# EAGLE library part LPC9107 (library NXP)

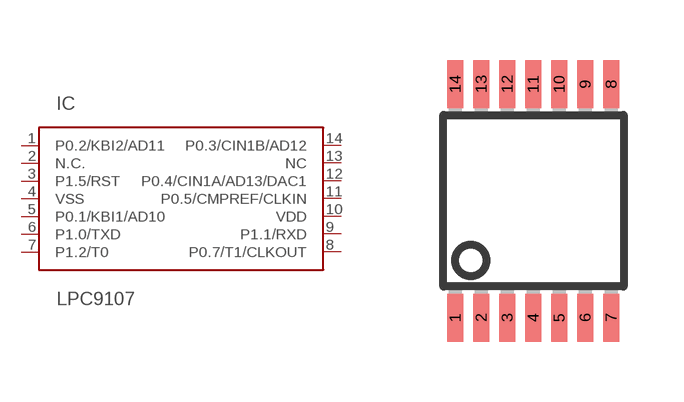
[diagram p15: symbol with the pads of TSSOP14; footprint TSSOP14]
Designator prefix IC

## LPC9107  [TSSOP14]
1  P0.2/KBI2/AD11
2  N.C.  nc
3  P1.5/RST
4  VSS
5  P0.1/KBI1/AD10
6  P1.0/TXD
7  P1.2/T0
8  P0.7/T1/CLKOUT
9  P1.1/RXD
10  VDD
11  P0.5/CMPREF/CLKIN
12  P0.4/CIN1A/AD13/DAC1
13  NC  nc
14  P0.3/CIN1B/AD12

## Footprint TSSOP14 (pad centres in mm)
smd 0.4 x 1.2: 1 -2.275,-2.925; 2 -1.625,-2.925; 3 -0.975,-2.925; 4 -0.325,-2.925; 5 0.325,-2.925; 6 0.975,-2.925; 7 1.625,-2.925; 8 1.625,2.925; 9 0.975,2.925; 10 0.325,2.925; 11 -0.325,2.925; 12 -0.975,2.925; 13 -1.625,2.925; 14 -2.275,2.925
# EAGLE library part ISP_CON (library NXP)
In System Programming connector for Philips ARM devices - /ISP and /RST must have pull up on uC side - /ISP is P0.14 on the LPC21xx chips - RxD is receive from uC, uC should driveTxD - 3,3V and 0V is supplied by the uC board - key is missing pin on a header, corresponding filled in the female plug for a ASP (anti smoke protection:)

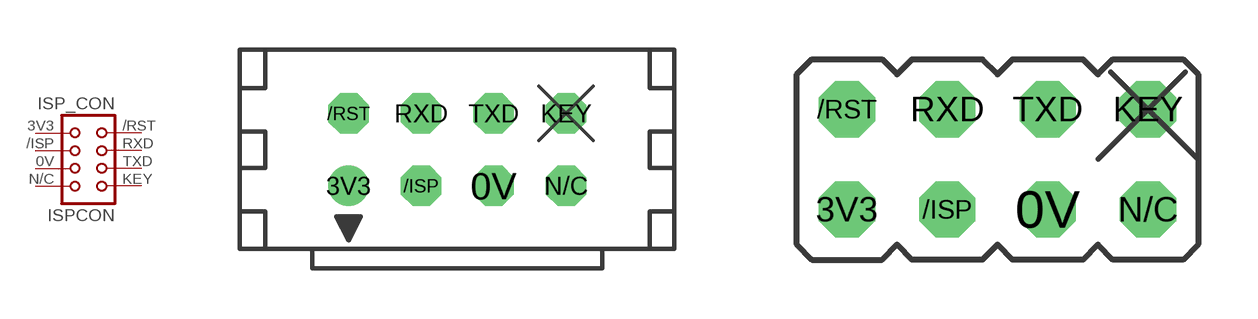
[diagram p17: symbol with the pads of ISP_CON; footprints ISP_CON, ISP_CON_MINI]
Designator prefix ISPCON

## ISP_CON  [ISP_CON]
0V  0V  pas
3V3  3V3  pas
/ISP  /ISP  pas
/RST  /RST  pas
KEY  KEY  pas
N/C  N/C  pas
RXD  RXD  pas
TXD  TXD  pas

## ISP_CONMINI  [ISP_CON_MINI]
Pads as for ISP_CON

## Footprint ISP_CON (pad centres in mm)
drill 0.914 octagon: 0V 1.27,-1.27; /ISP -1.27,-1.27; /RST -3.81,1.27; KEY 3.81,1.27; N/C 3.81,-1.27; RXD -1.27,1.27; TXD 1.27,1.27
drill 0.914 round: 3V3 -3.81,-1.27

## Footprint ISP_CON_MINI (pad centres in mm)
JUMPER
drill 0.914 octagon: 0V 1.27,-1.27; 3V3 -3.81,-1.27; /ISP -1.27,-1.27; /RST -3.81,1.27; KEY 3.81,1.27; N/C 3.81,-1.27; RXD -1.27,1.27; TXD 1.27,1.27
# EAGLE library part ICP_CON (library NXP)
ICP (In Circuit Programing ) connector for Philips LPC9XX 8052 devices

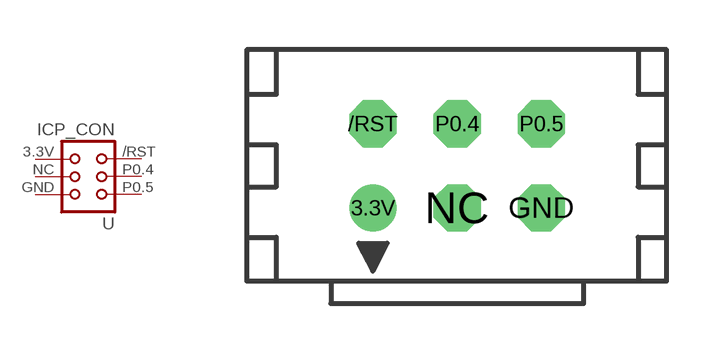
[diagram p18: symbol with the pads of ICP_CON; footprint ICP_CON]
Designator prefix -

## ICP_CON  [ICP_CON]
3.3V  3.3V  pas
/RST  /RST  pas
GND  GND  pas
NC  NC  pas
P0.4  P0.4  pas
P0.5  P0.5  pas

## Footprint ICP_CON (pad centres in mm)
drill 0.914 round: 3.3V -2.54,-1.27
drill 0.914 octagon: /RST -2.54,1.27; GND 2.54,-1.27; NC 0,-1.27; P0.4 0,1.27; P0.5 2.54,1.27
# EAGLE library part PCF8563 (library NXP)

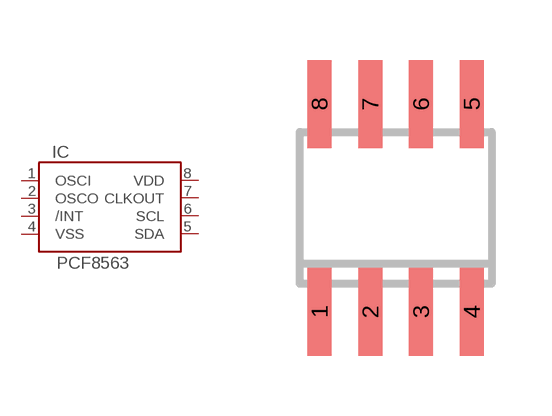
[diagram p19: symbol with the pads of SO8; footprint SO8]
Designator prefix IC

## PCF8563T  [SO8]
1  OSCI
2  OSCO
3  /INT
4  VSS
5  SDA
6  SCL
7  CLKOUT
8  VDD

## Footprint SO8 (pad centres in mm)
smd 0.6 x 2.2: 1 -1.905,-2.6; 2 -0.635,-2.6; 3 0.635,-2.6; 4 1.905,-2.6; 5 1.905,2.6; 6 0.635,2.6; 7 -0.635,2.6; 8 -1.905,2.6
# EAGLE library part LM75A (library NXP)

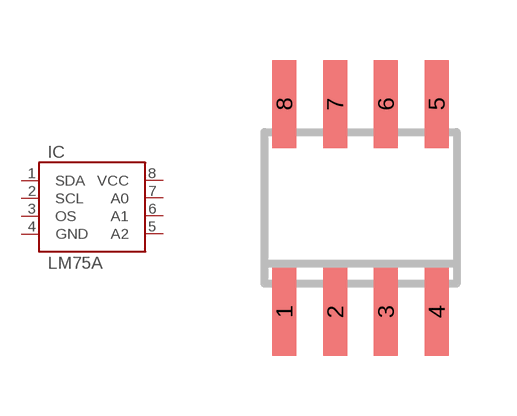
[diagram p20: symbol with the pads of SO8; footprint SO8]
Designator prefix IC

## LM75A  [SO8]
1  SDA
2  SCL
3  OS
4  GND
5  A2
6  A1
7  A0
8  VCC

## Footprint SO8 (pad centres in mm)
smd 0.6 x 2.2: 1 -1.905,-2.6; 2 -0.635,-2.6; 3 0.635,-2.6; 4 1.905,-2.6; 5 1.905,2.6; 6 0.635,2.6; 7 -0.635,2.6; 8 -1.905,2.6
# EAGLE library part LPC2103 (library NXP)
LPC2101/2102/2103 microcontroler from Philips

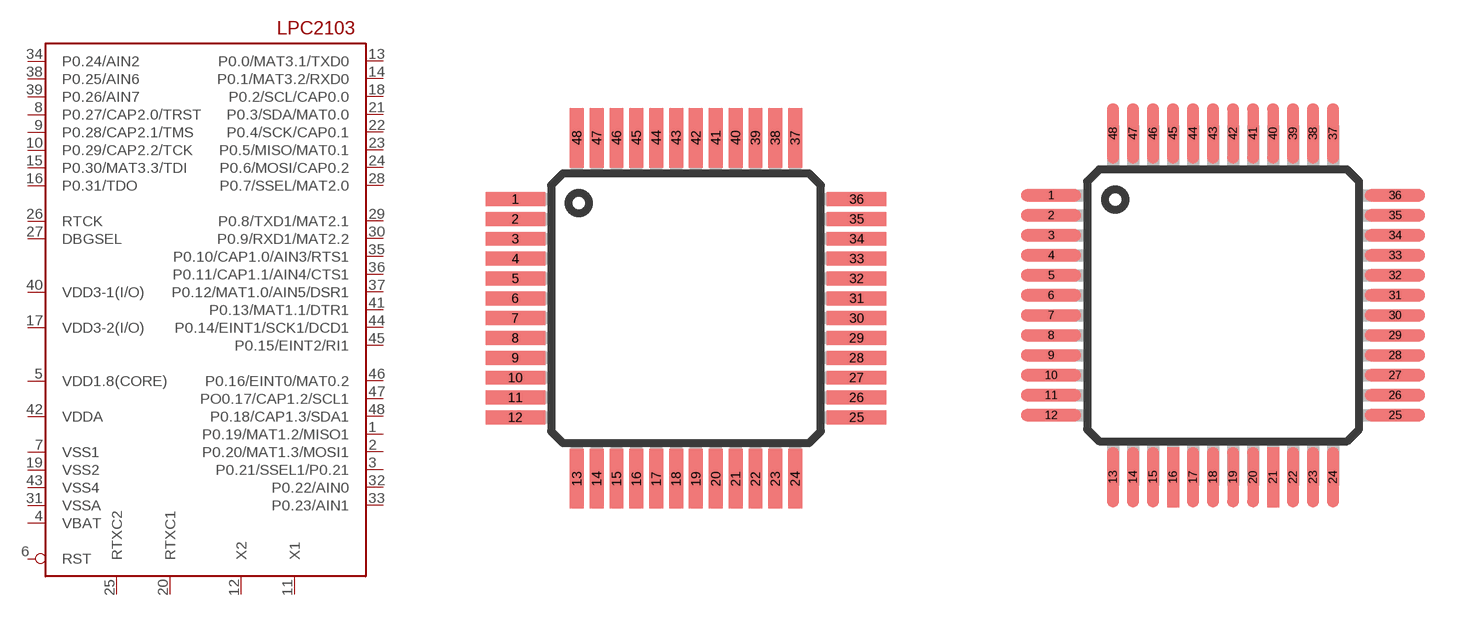
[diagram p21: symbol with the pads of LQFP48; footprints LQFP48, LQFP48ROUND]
Designator prefix IC

## LPC2103  [LQFP48]
1  P0.19/MAT1.2/MISO1
2  P0.20/MAT1.3/MOSI1
3  P0.21/SSEL1/P0.21
4  VBAT
5  VDD1.8(CORE)
6  RST
7  VSS1
8  P0.27/CAP2.0/TRST
9  P0.28/CAP2.1/TMS
10  P0.29/CAP2.2/TCK
11  X1
12  X2
13  P0.0/MAT3.1/TXD0
14  P0.1/MAT3.2/RXD0
15  P0.30/MAT3.3/TDI
16  P0.31/TDO
17  VDD3-2(I/O)
18  P0.2/SCL/CAP0.0
19  VSS2
20  RTXC1
21  P0.3/SDA/MAT0.0
22  P0.4/SCK/CAP0.1
23  P0.5/MISO/MAT0.1
24  P0.6/MOSI/CAP0.2
25  RTXC2
26  RTCK
27  DBGSEL
28  P0.7/SSEL/MAT2.0
29  P0.8/TXD1/MAT2.1
30  P0.9/RXD1/MAT2.2
31  VSSA
32  P0.22/AIN0
33  P0.23/AIN1
34  P0.24/AIN2
35  P0.10/CAP1.0/AIN3/RTS1
36  P0.11/CAP1.1/AIN4/CTS1
37  P0.12/MAT1.0/AIN5/DSR1
38  P0.25/AIN6
39  P0.26/AIN7
40  VDD3-1(I/O)
41  P0.13/MAT1.1/DTR1
42  VDDA
43  VSS4
44  P0.14/EINT1/SCK1/DCD1
45  P0.15/EINT2/RI1
46  P0.16/EINT0/MAT0.2
47  PO0.17/CAP1.2/SCL1
48  P0.18/CAP1.3/SDA1

## LPC2103ROUND  [LQFP48ROUND]
Pads as for LQFP48

## Footprint LQFP48 (pad centres in mm)
smd 1.5 x 0.35: 1 -4.3,2.75; 2 -4.3,2.25; 3 -4.3,1.75; 4 -4.3,1.25; 5 -4.3,0.75; 6 -4.3,0.25; 7 -4.3,-0.25; 8 -4.3,-0.75; 9 -4.3,-1.25; 10 -4.3,-1.75; 11 -4.3,-2.25; 12 -4.3,-2.75; 25 4.3,-2.75; 26 4.3,-2.25; 27 4.3,-1.75; 28 4.3,-1.25; 29 4.3,-0.75; 30 4.3,-0.25; 31 4.3,0.25; 32 4.3,0.75; 33 4.3,1.25; 34 4.3,1.75; 35 4.3,2.25; 36 4.3,2.75
smd 0.35 x 1.5: 13 -2.75,-4.3; 14 -2.25,-4.3; 15 -1.75,-4.3; 16 -1.25,-4.3; 17 -0.75,-4.3; 18 -0.25,-4.3; 19 0.25,-4.3; 20 0.75,-4.3; 21 1.25,-4.3; 22 1.75,-4.3; 23 2.25,-4.3; 24 2.75,-4.3; 37 2.75,4.3; 38 2.25,4.3; 39 1.75,4.3; 40 1.25,4.3; 41 0.75,4.3; 42 0.25,4.3; 43 -0.25,4.3; 44 -0.75,4.3; 45 -1.25,4.3; 46 -1.75,4.3; 47 -2.25,4.3; 48 -2.75,4.3

## Footprint LQFP48ROUND (pad centres in mm)
smd 1.5 x 0.3: 1 -4.3,2.75; 2 -4.3,2.25; 3 -4.3,1.75; 4 -4.3,1.25; 5 -4.3,0.75; 6 -4.3,0.25; 7 -4.3,-0.25; 8 -4.3,-0.75; 9 -4.3,-1.25; 10 -4.3,-1.75; 11 -4.3,-2.25; 12 -4.3,-2.75; 25 4.3,-2.75; 26 4.3,-2.25; 27 4.3,-1.75; 28 4.3,-1.25; 29 4.3,-0.75; 30 4.3,-0.25; 31 4.3,0.25; 32 4.3,0.75; 33 4.3,1.25; 34 4.3,1.75; 35 4.3,2.25; 36 4.3,2.75
smd 0.3 x 1.5: 13 -2.75,-4.3; 14 -2.25,-4.3; 15 -1.75,-4.3; 16 -1.25,-4.3; 17 -0.75,-4.3; 18 -0.25,-4.3; 19 0.25,-4.3; 20 0.75,-4.3; 21 1.25,-4.3; 22 1.75,-4.3; 23 2.25,-4.3; 24 2.75,-4.3; 37 2.75,4.3; 38 2.25,4.3; 39 1.75,4.3; 40 1.25,4.3; 41 0.75,4.3; 42 0.25,4.3; 43 -0.25,4.3; 44 -0.75,4.3; 45 -1.25,4.3; 46 -1.75,4.3; 47 -2.25,4.3; 48 -2.75,4.3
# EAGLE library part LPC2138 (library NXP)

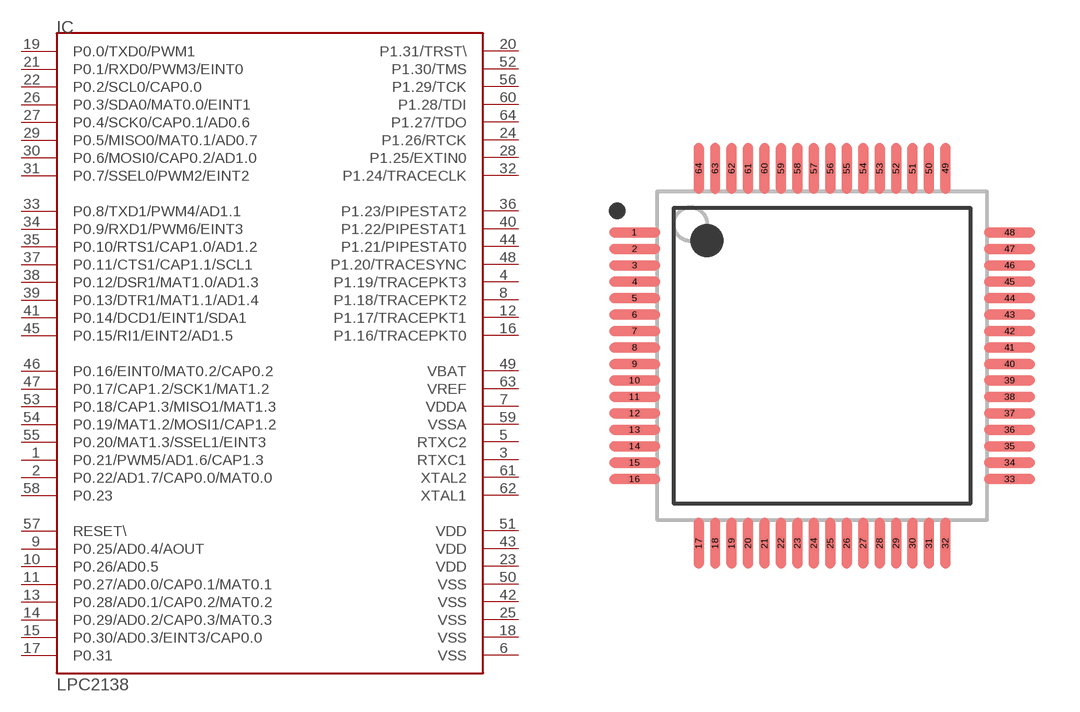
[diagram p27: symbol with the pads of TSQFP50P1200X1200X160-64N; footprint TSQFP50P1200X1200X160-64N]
Designator prefix IC

## LPC2138FBD64  [TSQFP50P1200X1200X160-64N]
1  P0.21/PWM5/AD1.6/CAP1.3
2  P0.22/AD1.7/CAP0.0/MAT0.0
3  RTXC1  in
4  P1.19/TRACEPKT3
5  RTXC2  out
6  VSS  pwr
7  VDDA  pwr
8  P1.18/TRACEPKT2
9  P0.25/AD0.4/AOUT
10  P0.26/AD0.5
11  P0.27/AD0.0/CAP0.1/MAT0.1
12  P1.17/TRACEPKT1
13  P0.28/AD0.1/CAP0.2/MAT0.2
14  P0.29/AD0.2/CAP0.3/MAT0.3
15  P0.30/AD0.3/EINT3/CAP0.0
16  P1.16/TRACEPKT0
17  P0.31
18  VSS  pwr
19  P0.0/TXD0/PWM1
20  P1.31/TRST\
21  P0.1/RXD0/PWM3/EINT0
22  P0.2/SCL0/CAP0.0
23  VDD  pwr
24  P1.26/RTCK
25  VSS  pwr
26  P0.3/SDA0/MAT0.0/EINT1
27  P0.4/SCK0/CAP0.1/AD0.6
28  P1.25/EXTIN0
29  P0.5/MISO0/MAT0.1/AD0.7
30  P0.6/MOSI0/CAP0.2/AD1.0
31  P0.7/SSEL0/PWM2/EINT2
32  P1.24/TRACECLK
33  P0.8/TXD1/PWM4/AD1.1
34  P0.9/RXD1/PWM6/EINT3
35  P0.10/RTS1/CAP1.0/AD1.2
36  P1.23/PIPESTAT2
37  P0.11/CTS1/CAP1.1/SCL1
38  P0.12/DSR1/MAT1.0/AD1.3
39  P0.13/DTR1/MAT1.1/AD1.4
40  P1.22/PIPESTAT1
41  P0.14/DCD1/EINT1/SDA1
42  VSS  pwr
43  VDD  pwr
44  P1.21/PIPESTAT0
45  P0.15/RI1/EINT2/AD1.5
46  P0.16/EINT0/MAT0.2/CAP0.2
47  P0.17/CAP1.2/SCK1/MAT1.2
48  P1.20/TRACESYNC
49  VBAT  pwr
50  VSS  pwr
51  VDD  pwr
52  P1.30/TMS
53  P0.18/CAP1.3/MISO1/MAT1.3
54  P0.19/MAT1.2/MOSI1/CAP1.2
55  P0.20/MAT1.3/SSEL1/EINT3
56  P1.29/TCK
57  RESET\  in
58  P0.23
59  VSSA  pwr
60  P1.28/TDI
61  XTAL2  out
62  XTAL1  in
63  VREF  in
64  P1.27/TDO

## Footprint TSQFP50P1200X1200X160-64N (pad centres in mm)
smd 1.55 x 0.3: 1 -5.7,3.75; 2 -5.7,3.25; 3 -5.7,2.75; 4 -5.7,2.25; 5 -5.7,1.75; 6 -5.7,1.25; 7 -5.7,0.75; 8 -5.7,0.25; 9 -5.7,-0.25; 10 -5.7,-0.75; 11 -5.7,-1.25; 12 -5.7,-1.75; 13 -5.7,-2.25; 14 -5.7,-2.75; 15 -5.7,-3.25; 16 -5.7,-3.75; 33 5.7,-3.75; 34 5.7,-3.25; 35 5.7,-2.75; 36 5.7,-2.25; 37 5.7,-1.75; 38 5.7,-1.25; 39 5.7,-0.75; 40 5.7,-0.25; 41 5.7,0.25; 42 5.7,0.75; 43 5.7,1.25; 44 5.7,1.75; 45 5.7,2.25; 46 5.7,2.75; 47 5.7,3.25; 48 5.7,3.75
smd 0.3 x 1.55: 17 -3.75,-5.7; 18 -3.25,-5.7; 19 -2.75,-5.7; 20 -2.25,-5.7; 21 -1.75,-5.7; 22 -1.25,-5.7; 23 -0.75,-5.7; 24 -0.25,-5.7; 25 0.25,-5.7; 26 0.75,-5.7; 27 1.25,-5.7; 28 1.75,-5.7; 29 2.25,-5.7; 30 2.75,-5.7; 31 3.25,-5.7; 32 3.75,-5.7; 49 3.75,5.7; 50 3.25,5.7; 51 2.75,5.7; 52 2.25,5.7; 53 1.75,5.7; 54 1.25,5.7; 55 0.75,5.7; 56 0.25,5.7; 57 -0.25,5.7; 58 -0.75,5.7; 59 -1.25,5.7; 60 -1.75,5.7; 61 -2.25,5.7; 62 -2.75,5.7; 63 -3.25,5.7; 64 -3.75,5.7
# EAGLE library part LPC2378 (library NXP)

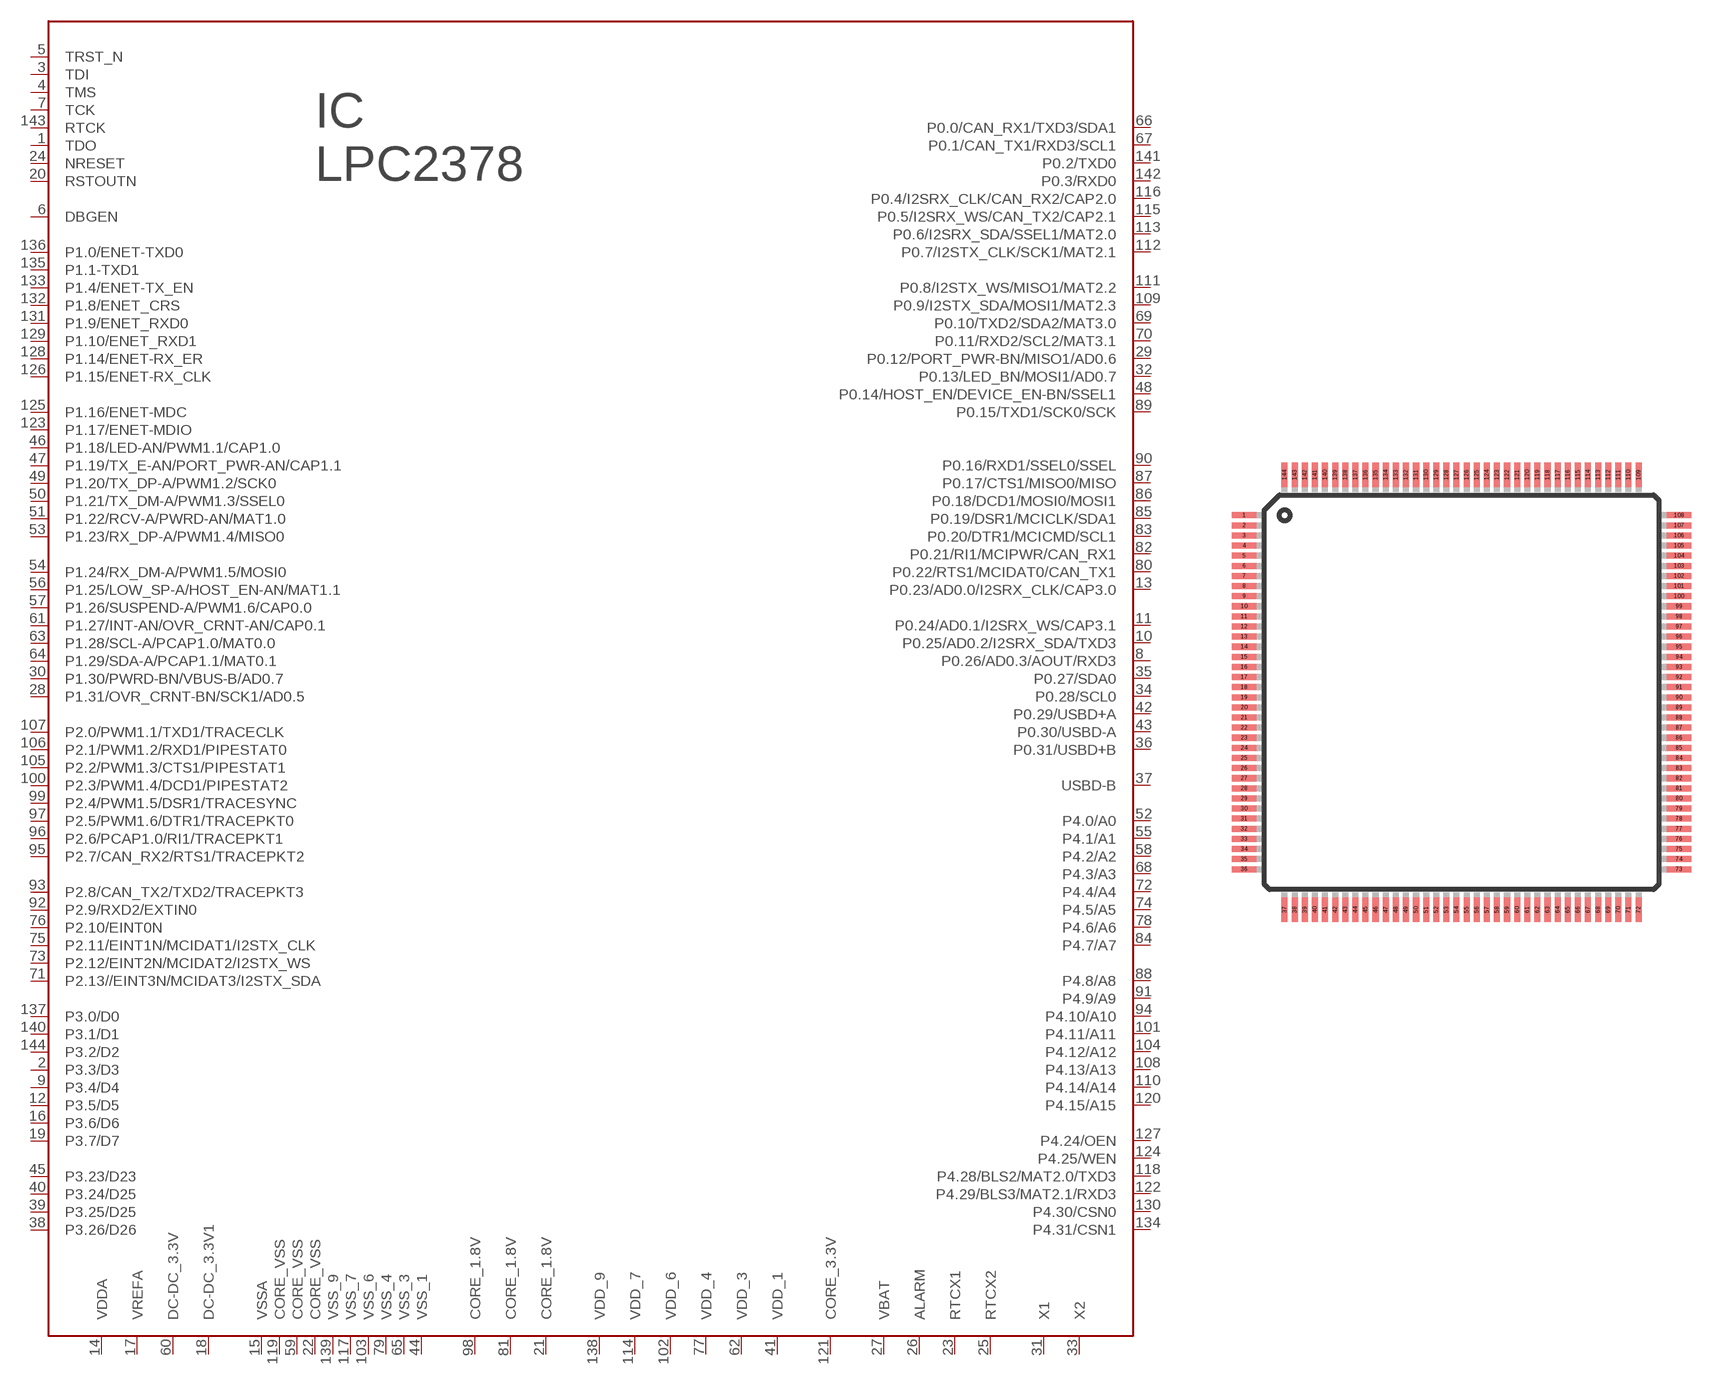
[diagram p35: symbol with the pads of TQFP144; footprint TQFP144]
Designator prefix IC

## LPC2378  [TQFP144]
1  TDO
2  P3.3/D3
3  TDI
4  TMS
5  TRST_N
6  DBGEN
7  TCK
8  P0.26/AD0.3/AOUT/RXD3
9  P3.4/D4
10  P0.25/AD0.2/I2SRX_SDA/TXD3
11  P0.24/AD0.1/I2SRX_WS/CAP3.1
12  P3.5/D5
13  P0.23/AD0.0/I2SRX_CLK/CAP3.0
14  VDDA
15  VSSA
16  P3.6/D6
17  VREFA
18  DC-DC_3.3V1
19  P3.7/D7
20  RSTOUTN
21  CORE_1.8V
22  CORE_VSS
23  RTCX1
24  NRESET
25  RTCX2
26  ALARM
27  VBAT
28  P1.31/OVR_CRNT-BN/SCK1/AD0.5
29  P0.12/PORT_PWR-BN/MISO1/AD0.6
30  P1.30/PWRD-BN/VBUS-B/AD0.7
31  X1
32  P0.13/LED_BN/MOSI1/AD0.7
33  X2
34  P0.28/SCL0
35  P0.27/SDA0
36  P0.31/USBD+B
37  USBD-B
38  P3.26/D26
39  P3.25/D25
40  P3.24/D25
41  VDD_1
42  P0.29/USBD+A
43  P0.30/USBD-A
44  VSS_1
45  P3.23/D23
46  P1.18/LED-AN/PWM1.1/CAP1.0
47  P1.19/TX_E-AN/PORT_PWR-AN/CAP1.1
48  P0.14/HOST_EN/DEVICE_EN-BN/SSEL1
49  P1.20/TX_DP-A/PWM1.2/SCK0
50  P1.21/TX_DM-A/PWM1.3/SSEL0
51  P1.22/RCV-A/PWRD-AN/MAT1.0
52  P4.0/A0
53  P1.23/RX_DP-A/PWM1.4/MISO0
54  P1.24/RX_DM-A/PWM1.5/MOSI0
55  P4.1/A1
56  P1.25/LOW_SP-A/HOST_EN-AN/MAT1.1
57  P1.26/SUSPEND-A/PWM1.6/CAP0.0
58  P4.2/A2
59  CORE_VSS
60  DC-DC_3.3V
61  P1.27/INT-AN/OVR_CRNT-AN/CAP0.1
62  VDD_3
63  P1.28/SCL-A/PCAP1.0/MAT0.0
64  P1.29/SDA-A/PCAP1.1/MAT0.1
65  VSS_3
66  P0.0/CAN_RX1/TXD3/SDA1
67  P0.1/CAN_TX1/RXD3/SCL1
68  P4.3/A3
69  P0.10/TXD2/SDA2/MAT3.0
70  P0.11/RXD2/SCL2/MAT3.1
71  P2.13//EINT3N/MCIDAT3/I2STX_SDA
72  P4.4/A4
73  P2.12/EINT2N/MCIDAT2/I2STX_WS
74  P4.5/A5
75  P2.11/EINT1N/MCIDAT1/I2STX_CLK
76  P2.10/EINT0N
77  VDD_4
78  P4.6/A6
79  VSS_4
80  P0.22/RTS1/MCIDAT0/CAN_TX1
81  CORE_1.8V
82  P0.21/RI1/MCIPWR/CAN_RX1
83  P0.20/DTR1/MCICMD/SCL1
84  P4.7/A7
85  P0.19/DSR1/MCICLK/SDA1
86  P0.18/DCD1/MOSI0/MOSI1
87  P0.17/CTS1/MISO0/MISO
88  P4.8/A8
89  P0.15/TXD1/SCK0/SCK
90  P0.16/RXD1/SSEL0/SSEL
91  P4.9/A9
92  P2.9/RXD2/EXTIN0
93  P2.8/CAN_TX2/TXD2/TRACEPKT3
94  P4.10/A10
95  P2.7/CAN_RX2/RTS1/TRACEPKT2
96  P2.6/PCAP1.0/RI1/TRACEPKT1
97  P2.5/PWM1.6/DTR1/TRACEPKT0
98  CORE_1.8V
99  P2.4/PWM1.5/DSR1/TRACESYNC
100  P2.3/PWM1.4/DCD1/PIPESTAT2
101  P4.11/A11
102  VDD_6
103  VSS_6
104  P4.12/A12
105  P2.2/PWM1.3/CTS1/PIPESTAT1
106  P2.1/PWM1.2/RXD1/PIPESTAT0
107  P2.0/PWM1.1/TXD1/TRACECLK
108  P4.13/A13
109  P0.9/I2STX_SDA/MOSI1/MAT2.3
110  P4.14/A14
111  P0.8/I2STX_WS/MISO1/MAT2.2
112  P0.7/I2STX_CLK/SCK1/MAT2.1
113  P0.6/I2SRX_SDA/SSEL1/MAT2.0
114  VDD_7
115  P0.5/I2SRX_WS/CAN_TX2/CAP2.1
116  P0.4/I2SRX_CLK/CAN_RX2/CAP2.0
117  VSS_7
118  P4.28/BLS2/MAT2.0/TXD3
119  CORE_VSS
120  P4.15/A15
121  CORE_3.3V
122  P4.29/BLS3/MAT2.1/RXD3
123  P1.17/ENET-MDIO
124  P4.25/WEN
125  P1.16/ENET-MDC
126  P1.15/ENET-RX_CLK
127  P4.24/OEN
128  P1.14/ENET-RX_ER
129  P1.10/ENET_RXD1
130  P4.30/CSN0
131  P1.9/ENET_RXD0
132  P1.8/ENET_CRS
133  P1.4/ENET-TX_EN
134  P4.31/CSN1
135  P1.1-TXD1
136  P1.0/ENET-TXD0
137  P3.0/D0
138  VDD_9
139  VSS_9
140  P3.1/D1
141  P0.2/TXD0
142  P0.3/RXD0
143  RTCK
144  P3.2/D2

## Footprint TQFP144 (pad centres in mm)
THIN QUAD FLAT PACK
smd 1.2 x 0.3: 1 -10.75,8.75; 2 -10.75,8.25; 3 -10.75,7.75; 4 -10.75,7.25; 5 -10.75,6.75; 6 -10.75,6.25; 7 -10.75,5.75; 8 -10.75,5.25; 9 -10.75,4.75; 10 -10.75,4.25; 11 -10.75,3.75; 12 -10.75,3.25; 13 -10.75,2.75; 14 -10.75,2.25; 15 -10.75,1.75; 16 -10.75,1.25; 17 -10.75,0.75; 18 -10.75,0.25; 19 -10.75,-0.25; 20 -10.75,-0.75; 21 -10.75,-1.25; 22 -10.75,-1.75; 23 -10.75,-2.25; 24 -10.75,-2.75; 25 -10.75,-3.25; 26 -10.75,-3.75; 27 -10.75,-4.25; 28 -10.75,-4.75; 29 -10.75,-5.25; 30 -10.75,-5.75; 31 -10.75,-6.25; 32 -10.75,-6.75; 33 -10.75,-7.25; 34 -10.75,-7.75; 35 -10.75,-8.25; 36 -10.75,-8.75; 73 10.75,-8.75; 74 10.75,-8.25; 75 10.75,-7.75; 76 10.75,-7.25; 77 10.75,-6.75; 78 10.75,-6.25; 79 10.75,-5.75; 80 10.75,-5.25; 81 10.75,-4.75; 82 10.75,-4.25; 83 10.75,-3.75; 84 10.75,-3.25; 85 10.75,-2.75; 86 10.75,-2.25; 87 10.75,-1.75; 88 10.75,-1.25; 89 10.75,-0.75; 90 10.75,-0.25; 91 10.75,0.25; 92 10.75,0.75; 93 10.75,1.25; 94 10.75,1.75; 95 10.75,2.25; 96 10.75,2.75; 97 10.75,3.25; 98 10.75,3.75; 99 10.75,4.25; 100 10.75,4.75; 101 10.75,5.25; 102 10.75,5.75; 103 10.75,6.25; 104 10.75,6.75; 105 10.75,7.25; 106 10.75,7.75; 107 10.75,8.25; 108 10.75,8.75
smd 0.3 x 1.2: 37 -8.75,-10.75; 38 -8.25,-10.75; 39 -7.75,-10.75; 40 -7.25,-10.75; 41 -6.75,-10.75; 42 -6.25,-10.75; 43 -5.75,-10.75; 44 -5.25,-10.75; 45 -4.75,-10.75; 46 -4.25,-10.75; 47 -3.75,-10.75; 48 -3.25,-10.75; 49 -2.75,-10.75; 50 -2.25,-10.75; 51 -1.75,-10.75; 52 -1.25,-10.75; 53 -0.75,-10.75; 54 -0.25,-10.75; 55 0.25,-10.75; 56 0.75,-10.75; 57 1.25,-10.75; 58 1.75,-10.75; 59 2.25,-10.75; 60 2.75,-10.75; 61 3.25,-10.75; 62 3.75,-10.75; 63 4.25,-10.75; 64 4.75,-10.75; 65 5.25,-10.75; 66 5.75,-10.75; 67 6.25,-10.75; 68 6.75,-10.75; 69 7.25,-10.75; 70 7.75,-10.75; 71 8.25,-10.75; 72 8.75,-10.75; 109 8.75,10.75; 110 8.25,10.75; 111 7.75,10.75; 112 7.25,10.75; 113 6.75,10.75; 114 6.25,10.75; 115 5.75,10.75; 116 5.25,10.75; 117 4.75,10.75; 118 4.25,10.75; 119 3.75,10.75; 120 3.25,10.75; 121 2.75,10.75; 122 2.25,10.75; 123 1.75,10.75; 124 1.25,10.75; 125 0.75,10.75; 126 0.25,10.75; 127 -0.25,10.75; 128 -0.75,10.75; 129 -1.25,10.75; 130 -1.75,10.75; 131 -2.25,10.75; 132 -2.75,10.75; 133 -3.25,10.75; 134 -3.75,10.75; 135 -4.25,10.75; 136 -4.75,10.75; 137 -5.25,10.75; 138 -5.75,10.75; 139 -6.25,10.75; 140 -6.75,10.75; 141 -7.25,10.75; 142 -7.75,10.75; 143 -8.25,10.75; 144 -8.75,10.75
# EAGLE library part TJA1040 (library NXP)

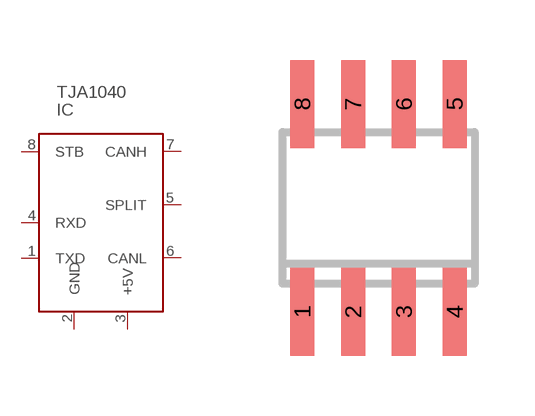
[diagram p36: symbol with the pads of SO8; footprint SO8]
Designator prefix IC

## TJA1040  [SO8]
1  TXD
2  GND
3  +5V
4  RXD
5  SPLIT
6  CANL
7  CANH
8  STB

## Footprint SO8 (pad centres in mm)
smd 0.6 x 2.2: 1 -1.905,-2.6; 2 -0.635,-2.6; 3 0.635,-2.6; 4 1.905,-2.6; 5 1.905,2.6; 6 0.635,2.6; 7 -0.635,2.6; 8 -1.905,2.6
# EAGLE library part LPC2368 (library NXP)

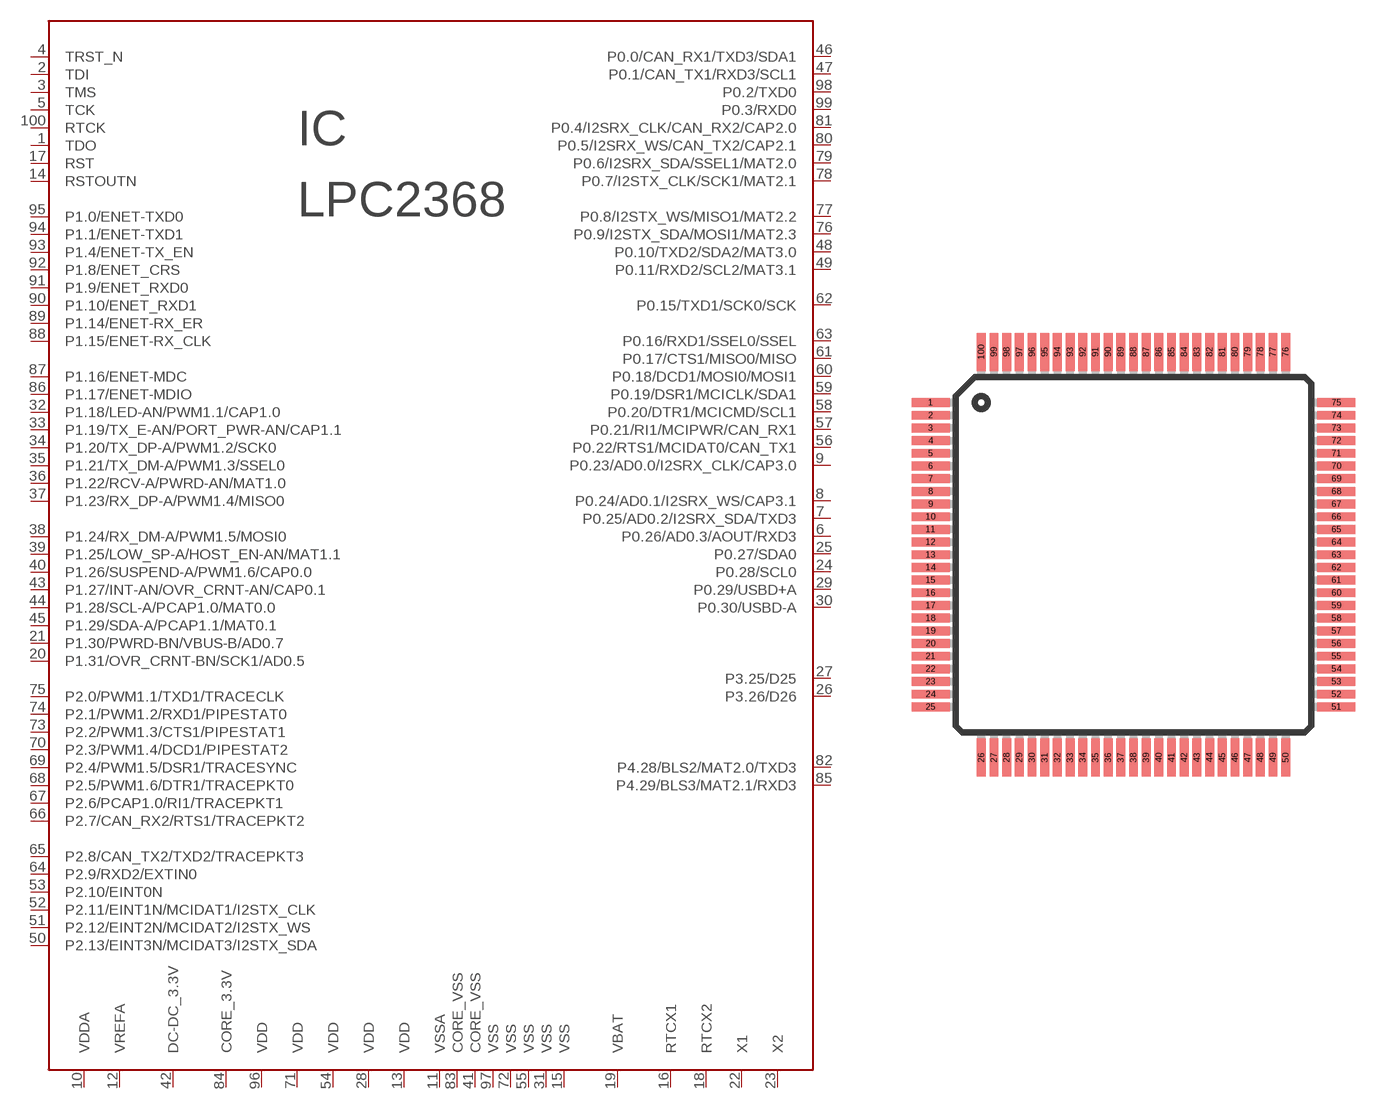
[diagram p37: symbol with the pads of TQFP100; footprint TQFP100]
Designator prefix IC

## LPC2368  [TQFP100]
1  TDO
2  TDI
3  TMS
4  TRST_N
5  TCK
6  P0.26/AD0.3/AOUT/RXD3
7  P0.25/AD0.2/I2SRX_SDA/TXD3
8  P0.24/AD0.1/I2SRX_WS/CAP3.1
9  P0.23/AD0.0/I2SRX_CLK/CAP3.0
10  VDDA
11  VSSA
12  VREFA
13  VDD
14  RSTOUTN
15  VSS
16  RTCX1
17  RST
18  RTCX2
19  VBAT
20  P1.31/OVR_CRNT-BN/SCK1/AD0.5
21  P1.30/PWRD-BN/VBUS-B/AD0.7
22  X1
23  X2
24  P0.28/SCL0
25  P0.27/SDA0
26  P3.26/D26
27  P3.25/D25
28  VDD
29  P0.29/USBD+A
30  P0.30/USBD-A
31  VSS
32  P1.18/LED-AN/PWM1.1/CAP1.0
33  P1.19/TX_E-AN/PORT_PWR-AN/CAP1.1
34  P1.20/TX_DP-A/PWM1.2/SCK0
35  P1.21/TX_DM-A/PWM1.3/SSEL0
36  P1.22/RCV-A/PWRD-AN/MAT1.0
37  P1.23/RX_DP-A/PWM1.4/MISO0
38  P1.24/RX_DM-A/PWM1.5/MOSI0
39  P1.25/LOW_SP-A/HOST_EN-AN/MAT1.1
40  P1.26/SUSPEND-A/PWM1.6/CAP0.0
41  CORE_VSS
42  DC-DC_3.3V
43  P1.27/INT-AN/OVR_CRNT-AN/CAP0.1
44  P1.28/SCL-A/PCAP1.0/MAT0.0
45  P1.29/SDA-A/PCAP1.1/MAT0.1
46  P0.0/CAN_RX1/TXD3/SDA1
47  P0.1/CAN_TX1/RXD3/SCL1
48  P0.10/TXD2/SDA2/MAT3.0
49  P0.11/RXD2/SCL2/MAT3.1
50  P2.13/EINT3N/MCIDAT3/I2STX_SDA
51  P2.12/EINT2N/MCIDAT2/I2STX_WS
52  P2.11/EINT1N/MCIDAT1/I2STX_CLK
53  P2.10/EINT0N
54  VDD
55  VSS
56  P0.22/RTS1/MCIDAT0/CAN_TX1
57  P0.21/RI1/MCIPWR/CAN_RX1
58  P0.20/DTR1/MCICMD/SCL1
59  P0.19/DSR1/MCICLK/SDA1
60  P0.18/DCD1/MOSI0/MOSI1
61  P0.17/CTS1/MISO0/MISO
62  P0.15/TXD1/SCK0/SCK
63  P0.16/RXD1/SSEL0/SSEL
64  P2.9/RXD2/EXTIN0
65  P2.8/CAN_TX2/TXD2/TRACEPKT3
66  P2.7/CAN_RX2/RTS1/TRACEPKT2
67  P2.6/PCAP1.0/RI1/TRACEPKT1
68  P2.5/PWM1.6/DTR1/TRACEPKT0
69  P2.4/PWM1.5/DSR1/TRACESYNC
70  P2.3/PWM1.4/DCD1/PIPESTAT2
71  VDD
72  VSS
73  P2.2/PWM1.3/CTS1/PIPESTAT1
74  P2.1/PWM1.2/RXD1/PIPESTAT0
75  P2.0/PWM1.1/TXD1/TRACECLK
76  P0.9/I2STX_SDA/MOSI1/MAT2.3
77  P0.8/I2STX_WS/MISO1/MAT2.2
78  P0.7/I2STX_CLK/SCK1/MAT2.1
79  P0.6/I2SRX_SDA/SSEL1/MAT2.0
80  P0.5/I2SRX_WS/CAN_TX2/CAP2.1
81  P0.4/I2SRX_CLK/CAN_RX2/CAP2.0
82  P4.28/BLS2/MAT2.0/TXD3
83  CORE_VSS
84  CORE_3.3V
85  P4.29/BLS3/MAT2.1/RXD3
86  P1.17/ENET-MDIO
87  P1.16/ENET-MDC
88  P1.15/ENET-RX_CLK
89  P1.14/ENET-RX_ER
90  P1.10/ENET_RXD1
91  P1.9/ENET_RXD0
92  P1.8/ENET_CRS
93  P1.4/ENET-TX_EN
94  P1.1/ENET-TXD1
95  P1.0/ENET-TXD0
96  VDD
97  VSS
98  P0.2/TXD0
99  P0.3/RXD0
100  RTCK

## Footprint TQFP100 (pad centres in mm)
Thin Quad Flat Package
smd 1.5 x 0.35: 1 -8,6; 2 -8,5.5; 3 -8,5; 4 -8,4.5; 5 -8,4; 6 -8,3.5; 7 -8,3; 8 -8,2.5; 9 -8,2; 10 -8,1.5; 11 -8,1; 12 -8,0.5; 13 -8,0; 14 -8,-0.5; 15 -8,-1; 16 -8,-1.5; 17 -8,-2; 18 -8,-2.5; 19 -8,-3; 20 -8,-3.5; 21 -8,-4; 22 -8,-4.5; 23 -8,-5; 24 -8,-5.5; 25 -8,-6; 51 8,-6; 52 8,-5.5; 53 8,-5; 54 8,-4.5; 55 8,-4; 56 8,-3.5; 57 8,-3; 58 8,-2.5; 59 8,-2; 60 8,-1.5; 61 8,-1; 62 8,-0.5; 63 8,0; 64 8,0.5; 65 8,1; 66 8,1.5; 67 8,2; 68 8,2.5; 69 8,3; 70 8,3.5; 71 8,4; 72 8,4.5; 73 8,5; 74 8,5.5; 75 8,6
smd 0.35 x 1.5: 26 -6,-8; 27 -5.5,-8; 28 -5,-8; 29 -4.5,-8; 30 -4,-8; 31 -3.5,-8; 32 -3,-8; 33 -2.5,-8; 34 -2,-8; 35 -1.5,-8; 36 -1,-8; 37 -0.5,-8; 38 0,-8; 39 0.5,-8; 40 1,-8; 41 1.5,-8; 42 2,-8; 43 2.5,-8; 44 3,-8; 45 3.5,-8; 46 4,-8; 47 4.5,-8; 48 5,-8; 49 5.5,-8; 50 6,-8; 76 6,8; 77 5.5,8; 78 5,8; 79 4.5,8; 80 4,8; 81 3.5,8; 82 3,8; 83 2.5,8; 84 2,8; 85 1.5,8; 86 1,8; 87 0.5,8; 88 0,8; 89 -0.5,8; 90 -1,8; 91 -1.5,8; 92 -2,8; 93 -2.5,8; 94 -3,8; 95 -3.5,8; 96 -4,8; 97 -4.5,8; 98 -5,8; 99 -5.5,8; 100 -6,8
